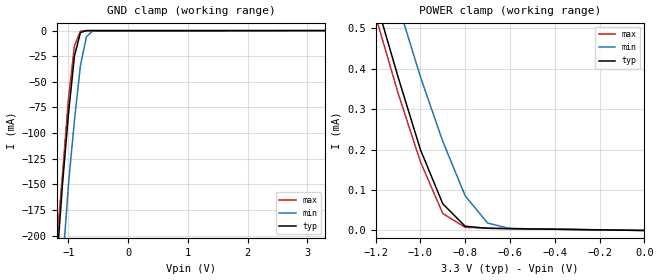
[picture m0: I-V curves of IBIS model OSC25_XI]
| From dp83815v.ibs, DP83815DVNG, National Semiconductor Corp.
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|   Model OSC25_XI
[Model]   OSC25_XI
Model_type   Input
Polarity   Non-Inverting
Enable   Active-High
Vinl =   0.80V
Vinh =   2.00V
Vmeas =   1.50V
Cref =  10.00pF
Rref = 100.00k
C_comp   5.00pF   5.00pF   5.00pF
[Temperature Range]   25.00   0.14k   0.000
[Voltage Range]   3.30V   3.00V   3.60V
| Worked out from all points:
|   GND clamp passes 1 mA (typ) near -0.75 V on its own axis
|   POWER clamp passes 1 mA (typ) near -1.42 V on its own axis
[GND_clamp]
| voltage   I(typ)   I(min)   I(max)
-3.3V     -1.95A     -2.01A     -1.94A
-1.2V     -230mA     -300mA     -210mA
-1.1V     -150mA     -230mA     -140mA
-1V       -81.16mA   -150mA     -66.42mA
-900mV    -24.85mA   -87.47mA   -14.78mA
-800mV    -1.91mA    -34.09mA   -620uA
-700mV    -82.09uA   -6.17mA    -39.22uA
-600mV    -23.98uA   -580uA     -25.91uA
3.3V      7.12pA     1.71uA     -2.08uA
[POWER_clamp]
| voltage   I(typ)   I(min)   I(max)
-3.3V     4.86mA     5.01mA     4.83mA
-1.2V     570uA      750uA      530uA
-1.1V     380uA      560uA      340uA
-1V       200uA      380uA      170uA
-900mV    65.83uA    220uA      41.88uA
-800mV    10.38uA    85.67uA    7.76uA
-700mV    5.42uA     18.36uA    5.61uA
-600mV    4.5uA      4.85uA     4.76uA
0V        7.12pA     140pA      7.77pA
